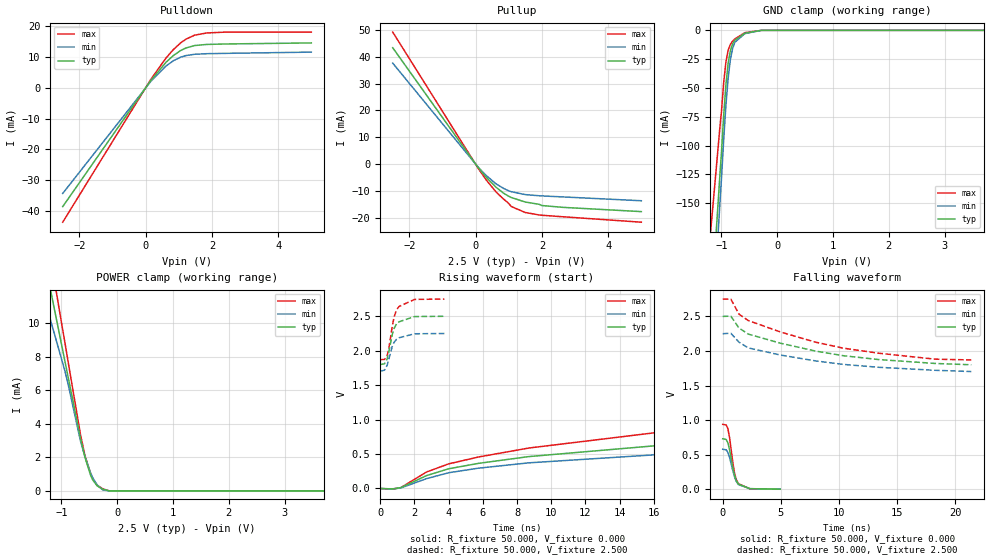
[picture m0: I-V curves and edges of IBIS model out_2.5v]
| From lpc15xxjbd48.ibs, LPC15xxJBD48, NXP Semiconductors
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[Model]   out_2.5v
Model_type I/O
Vinl=7.500E-01
Vinh=1.750E+00
Vref=0.000E+00
Rref=1.000E+06
Cref=0.000E+00
Vmeas=1.250E+00
C_comp   5.980E-13   5.980E-13   5.980E-13
[Voltage Range]   2.500E+00   2.250E+00   2.750E+00
[POWER Clamp Reference]   2.500E+00   2.250E+00   2.750E+00
[GND Clamp Reference]   0.000E+00   0.000E+00   0.000E+00
[Pullup Reference]   2.500E+00   2.250E+00   2.750E+00
[Pulldown Reference]   0.000E+00   0.000E+00   0.000E+00
[Temperature Range]   25   85   -40
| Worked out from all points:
|   slope of the pulldown table from 0 to 0.375 V, typ, clamps not added: 70.8 ohm
|   slope of the pullup table from 0 to 0.375 V, typ, clamps not added: 66.4 ohm
|   GND clamp passes 1 mA (typ) near -0.49 V on its own axis
|   POWER clamp passes 1 mA (typ) near -0.48 V on its own axis
|   rising waveform, R_fixture 50.000, V_fixture 0.000: 20-80 % time 11.5ns typ, 11.2ns min, 11.5ns max; typ from 0 V to 0.729 V
|   falling waveform, R_fixture 50.000, V_fixture 0.000: 20-80 % time 536ps typ, 573ps min, 492ps max; typ from 0.729 V to 0 V
|   rising waveform, R_fixture 50.000, V_fixture 2.500: 20-80 % time 411ps typ, 424ps min, 407ps max; typ from 1.8 V to 2.5 V
|   falling waveform, R_fixture 50.000, V_fixture 2.500: 20-80 % time 8.8ns typ, 8.76ns min, 8.95ns max; typ from 2.5 V to 1.8 V
[GND Clamp]
-2.5V     -1.219A    -1.334A    -886mA
-1.02V    -120mA     -144.3mA   -80.04mA
-1V       -106.5mA   -129.2mA   -70.92mA
-960mV    -73.92mA   -95.1mA    -45.49mA
-920mV    -47.27mA   -65.11mA   -27.49mA
-880mV    -28.66mA   -41.65mA   -17.27mA
-840mV    -17.58mA   -25.47mA   -12.14mA
-800mV    -11.7mA    -15.74mA   -9.357mA
-760mV    -8.541mA   -10.37mA   -7.463mA
-580mV    -2.501mA   -2.825mA   -2.036mA
-280mV    0A         0A         0A
5V        0A         0A         0A
[Power Clamp]
-2.5V     33.44mA    25.55mA    39.59mA
-2.46V    32.78mA    25mA       38.69mA
-940mV    7.765mA    7.172mA    8.87mA
-880mV    6.778mA    6.354mA    7.693mA
-660mV    3.162mA    2.985mA    3.377mA
-580mV    2.015mA    2.057mA    2.115mA
-480mV    959.5uA    1.086mA    1.07mA
-440mV    661.8uA    786.1uA    746.8uA
-360mV    301.5uA    349uA      347.2uA
-260mV    106.3uA    61.77uA    124.7uA
-140mV    0A         0A         0A
5V        0A         0A         0A
[Pullup]
-2.5V     43.37mA    37.65mA    49.21mA
80mV      -1.276mA   -1.15mA    -1.562mA
320mV     -4.893mA   -4.216mA   -5.866mA
620mV     -8.619mA   -7.349mA   -10.37mA
840mV     -10.76mA   -9mA       -12.96mA
980mV     -11.81mA   -9.814mA   -14.39mA
1.08V     -12.43mA   -10.27mA   -15.78mA
1.5V      -14.1mA    -11.33mA   -18mA
1.92V     -14.95mA   -11.76mA   -18.93mA
2V        -15.4mA    -11.82mA   -19.03mA
2.62V     -16.07mA   -12.19mA   -19.58mA
5V        -17.67mA   -13.62mA   -21.61mA
[Pulldown]
-2.5V     -38.5mA    -34.24mA   -43.55mA
160mV     2.38mA     2.079mA    2.732mA
620mV     8.285mA    7.065mA    9.692mA
840mV     10.45mA    8.77mA     12.37mA
1.06V     12.07mA    9.914mA    14.55mA
1.22V     12.89mA    10.43mA    15.75mA
1.48V     13.67mA    10.84mA    17.03mA
1.84V     14.03mA    11.03mA    17.74mA
2.42V     14.18mA    11.14mA    18.03mA
5V        14.52mA    11.54mA    18.03mA
[Rising Waveform]
R_fixture = 50.000
V_fixture = 0.000
V_fixture_min = 0.000
V_fixture_max = 0.000
|  time   V(typ)   V(min)   V(max)
0s        0V         0V         0V
700ps     -6.201mV   -6.922mV   -9.806mV
1.2ns     12.59mV    7.396mV    12.07mV
2.7ns     186.5mV    142.6mV    238.7mV
4ns       286.2mV    228.6mV    357.4mV
5.75ns    365mV      295.2mV    457.6mV
8.7ns     463.4mV    372.5mV    587.6mV
17.95ns   660mV      518.6mV    866.2mV
20.55ns   699.7mV    549.6mV    911.1mV
24.2ns    728.9mV    577.3mV    937.8mV
[Falling Waveform]
R_fixture = 50.000
V_fixture = 0.000
V_fixture_min = 0.000
V_fixture_max = 0.000
|  time   V(typ)   V(min)   V(max)
0s        728.9mV    577.3mV    937.8mV
300ps     718.8mV    569.4mV    929.3mV
450ps     669.6mV    530.6mV    872.6mV
600ps     564.6mV    452.6mV    736.5mV
850ps     331.6mV    281.2mV    412.2mV
1ns       210.9mV    186.5mV    249mV
1.15ns    129.1mV    117.8mV    145.2mV
1.35ns    72.42mV    66.55mV    78.97mV
2.35ns    6.985mV    7.177mV    3.888mV
4.95ns    0V         0V         0V
[Rising Waveform]
R_fixture = 50.000
V_fixture = 2.500
V_fixture_min = 2.250
V_fixture_max = 2.750
|  time   V(typ)   V(min)   V(max)
0s        1.8V       1.702V     1.87V
250ps     1.81V      1.718V     1.874V
400ps     1.88V      1.788V     1.926V
500ps     1.984V     1.877V     2.032V
700ps     2.234V     2.061V     2.352V
800ps     2.32V      2.119V     2.481V
950ps     2.389V     2.166V     2.593V
1.1ns     2.42V      2.188V     2.642V
2ns       2.496V     2.246V     2.745V
3.75ns    2.5V       2.25V      2.75V
[Falling Waveform]
R_fixture = 50.000
V_fixture = 2.500
V_fixture_min = 2.250
V_fixture_max = 2.750
|  time   V(typ)   V(min)   V(max)
0s        2.5V       2.25V      2.75V
700ps     2.504V     2.256V     2.751V
1.4ns     2.332V     2.127V     2.533V
2.2ns     2.244V     2.044V     2.44V
5ns       2.111V     1.94V      2.273V
8ns       1.998V     1.856V     2.127V
10.4ns    1.931V     1.805V     2.04V
13.4ns    1.876V     1.764V     1.968V
18.3ns    1.819V     1.72V      1.881V
21.4ns    1.8V       1.702V     1.87V
[Ramp]
dV/dt_r   4.3349E-01/1.1503E-08   3.4248E-01/1.1204E-08   5.6014E-01/1.1504E-08
dV/dt_f   4.2023E-01/8.7836E-09   3.2909E-01/8.7480E-09   5.2784E-01/8.9441E-09
R_load = 50
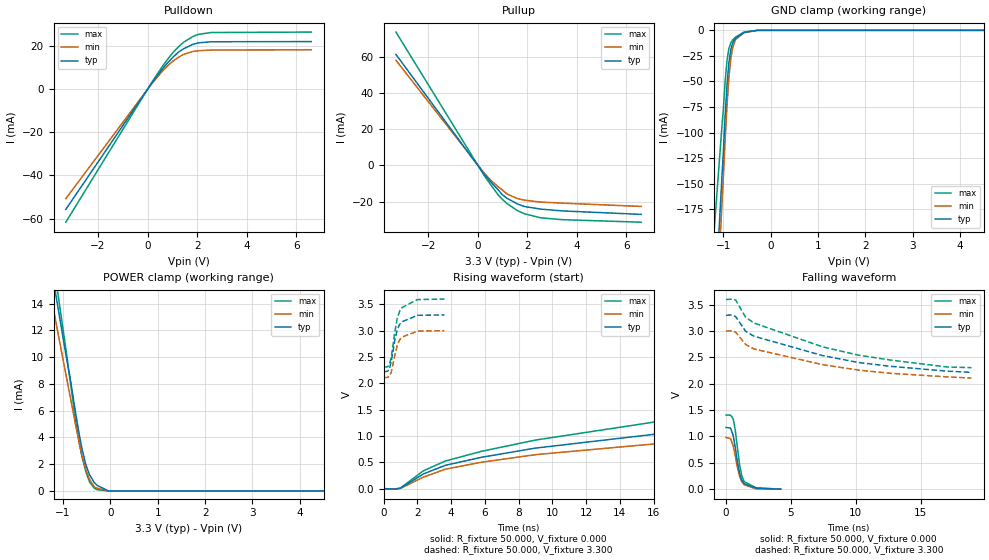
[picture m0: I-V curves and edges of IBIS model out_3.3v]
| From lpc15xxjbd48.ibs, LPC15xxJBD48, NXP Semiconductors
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[Model]   out_3.3v
Model_type I/O
Vinl=9.900E-01
Vinh=2.310E+00
Vref=0.000E+00
Rref=1.000E+06
Cref=0.000E+00
Vmeas=1.650E+00
C_comp   5.980E-13   5.980E-13   5.980E-13
[Voltage Range]   3.300E+00   3.000E+00   3.600E+00
[POWER Clamp Reference]   3.300E+00   3.000E+00   3.600E+00
[GND Clamp Reference]   0.000E+00   0.000E+00   0.000E+00
[Pullup Reference]   3.300E+00   3.000E+00   3.600E+00
[Pulldown Reference]   0.000E+00   0.000E+00   0.000E+00
[Temperature Range]   25   85   -40
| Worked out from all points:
|   slope of the pulldown table from 0 to 0.495 V, typ, clamps not added: 63.4 ohm
|   slope of the pullup table from 0 to 0.495 V, typ, clamps not added: 56.7 ohm
|   GND clamp passes 1 mA (typ) near -0.49 V on its own axis
|   POWER clamp passes 1 mA (typ) near -0.41 V on its own axis
|   rising waveform, R_fixture 50.000, V_fixture 0.000: 20-80 % time 11.2ns typ, 11.2ns min, 11ns max; typ from 0 V to 1.17 V
|   falling waveform, R_fixture 50.000, V_fixture 0.000: 20-80 % time 503ps typ, 524ps min, 476ps max; typ from 1.17 V to 0 V
|   rising waveform, R_fixture 50.000, V_fixture 3.300: 20-80 % time 423ps typ, 429ps min, 420ps max; typ from 2.22 V to 3.3 V
|   falling waveform, R_fixture 50.000, V_fixture 3.300: 20-80 % time 8.24ns typ, 8.16ns min, 8.44ns max; typ from 3.3 V to 2.22 V
[GND Clamp]
-3.3V     -2.092A    -2.24A     -1.503A
-1.02V    -136.5mA   -162.9mA   -89.08mA
-1V       -121mA     -145.6mA   -78.71mA
-960mV    -83.35mA   -107.1mA   -49.72mA
-920mV    -52.59mA   -72.89mA   -29.28mA
-880mV    -31.29mA   -46.03mA   -17.86mA
-840mV    -18.71mA   -27.63mA   -12.25mA
-800mV    -12.16mA   -16.61mA   -9.308mA
-740mV    -7.606mA   -8.868mA   -6.601mA
-560mV    -2.076mA   -2.347mA   -1.597mA
-280mV    0A         0A         0A
6.6V      0A         0A         0A
[Power Clamp]
-3.3V     60.1mA     52.45mA    68.25mA
-960mV    10.62mA    9.102mA    11.13mA
-840mV    8.232mA    6.892mA    8.008mA
-740mV    5.956mA    5.041mA    5.421mA
-660mV    4.276mA    3.656mA    3.63mA
-600mV    3.161mA    2.657mA    2.579mA
-520mV    1.98mA     1.612mA    1.469mA
-440mV    1.21mA     855.2uA    675.1uA
-340mV    627uA      307.8uA    207.7uA
-280mV    412.7uA    202.8uA    95.13uA
-40mV     0A         0A         0A
6.6V      0A         0A         0A
[Pullup]
-3.3V     61.34mA    58.13mA    73.7mA
260mV     -4.829mA   -4.262mA   -5.613mA
520mV     -9.132mA   -8.123mA   -10.64mA
820mV     -13.48mA   -11.81mA   -16.28mA
980mV     -16.07mA   -13.46mA   -18.64mA
1.18V     -18.21mA   -15.84mA   -21.11mA
1.6V      -21.35mA   -18.37mA   -25.05mA
1.88V     -22.76mA   -19.26mA   -26.76mA
2.54V     -24.21mA   -20.31mA   -29.02mA
3.44V     -25.22mA   -20.92mA   -30.07mA
6.6V      -27.13mA   -22.73mA   -31.44mA
[Pulldown]
-3.3V     -55.7mA    -50.74mA   -61.64mA
160mV     2.667mA    2.408mA    2.982mA
600mV     9.417mA    8.409mA    10.62mA
840mV     12.61mA    11.17mA    14.31mA
1.04V     15mA       13.18mA    17.2mA
1.24V     17.11mA    14.74mA    19.56mA
1.44V     18.66mA    16.07mA    21.64mA
1.82V     20.75mA    17.47mA    24.39mA
2.06V     21.46mA    17.82mA    25.42mA
2.56V     21.97mA    18.13mA    26.25mA
6.6V      22.05mA    18.25mA    26.45mA
[Rising Waveform]
R_fixture = 50.000
V_fixture = 0.000
V_fixture_min = 0.000
V_fixture_max = 0.000
|  time   V(typ)   V(min)   V(max)
0s        0V         0V         0V
650ps     -10.73mV   -8.915mV   -10.84mV
1ns       10.16mV    3.021mV    11.92mV
2.35ns    276.6mV    217.2mV    337.4mV
3.65ns    441.9mV    367.9mV    523.2mV
5.8ns     595.1mV    501.3mV    708.2mV
9ns       769.2mV    644.6mV    921.9mV
16.8ns    1.06V      870.9mV    1.301V
19.9ns    1.135V     941.1mV    1.375V
23.9ns    1.172V     980.8mV    1.406V
[Falling Waveform]
R_fixture = 50.000
V_fixture = 0.000
V_fixture_min = 0.000
V_fixture_max = 0.000
|  time   V(typ)   V(min)   V(max)
0s        1.172V     980.8mV    1.406V
350ps     1.158V     958.8mV    1.405V
550ps     1.02V      823.8mV    1.333V
700ps     805.6mV    643.9mV    1.139V
900ps     479.8mV    386.4mV    738.8mV
1.05ns    292.8mV    238.8mV    454.7mV
1.2ns     178.5mV    145.6mV    264.5mV
1.4ns     105.2mV    83.16mV    142.8mV
2.3ns     19.47mV    6.645mV    27.16mV
4.2ns     0V         0V         0V
[Rising Waveform]
R_fixture = 50.000
V_fixture = 3.300
V_fixture_min = 3.000
V_fixture_max = 3.600
|  time   V(typ)   V(min)   V(max)
0s        2.218V     2.108V     2.306V
250ps     2.232V     2.114V     2.315V
350ps     2.285V     2.14V      2.363V
450ps     2.412V     2.213V     2.492V
650ps     2.799V     2.508V     2.95V
800ps     3.014V     2.715V     3.229V
950ps     3.12V      2.828V     3.373V
1.1ns     3.17V      2.88V      3.441V
2ns       3.291V     2.991V     3.59V
3.6ns     3.3V       3V         3.6V
[Falling Waveform]
R_fixture = 50.000
V_fixture = 3.300
V_fixture_min = 3.000
V_fixture_max = 3.600
|  time   V(typ)   V(min)   V(max)
0s        3.3V       3V         3.6V
500ps     3.307V     3.007V     3.608V
750ps     3.273V     2.977V     3.587V
1.5ns     2.998V     2.747V     3.266V
2.15ns    2.903V     2.661V     3.153V
7.45ns    2.534V     2.362V     2.7V
10.2ns    2.404V     2.26V      2.543V
12.65ns   2.332V     2.199V     2.451V
17.05ns   2.239V     2.131V     2.318V
18.9ns    2.218V     2.108V     2.306V
[Ramp]
dV/dt_r   7.0008E-01/1.1253E-08   5.8704E-01/1.1245E-08   8.3940E-01/1.1024E-08
dV/dt_f   6.4925E-01/8.2596E-09   5.3506E-01/8.1712E-09   7.7641E-01/8.4454E-09
R_load = 50
